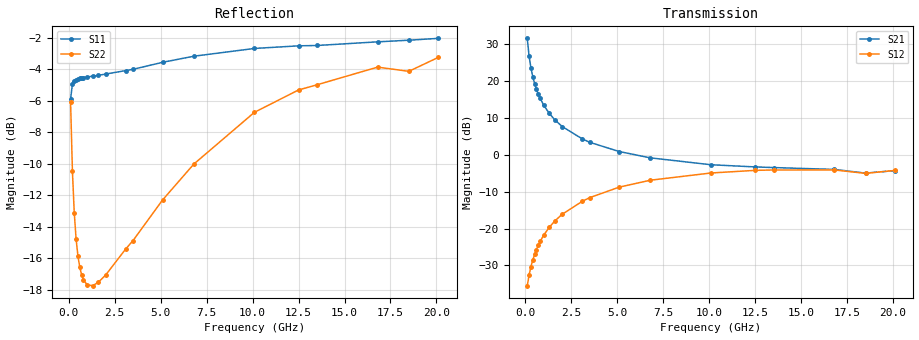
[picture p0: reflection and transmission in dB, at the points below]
!  Infineon Technologies AG
! BFR380L3 , PF131585-7, No.6, Th 09.10.01, soldered on pcb-board, measured with PP GSG850
!  Vce=2.0 V,  Ic=75.0 mA
! Common Emitter S-Parameters:  15. November 2001
#  GHz  S  MA  R  50
! f  S11  S21  S12  S22
! GHz  Mag  Ang  Mag  Ang  Mag  Ang  Mag  Ang
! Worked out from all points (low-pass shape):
!   201 points, 100 MHz to 20.1 GHz, reference 50 ohm
!   highest |S21| = 31.65 dB at 100 MHz (marker M1); lowest = -4.9 dB at 18.5 GHz (marker M2)
!   |S21| within 3 dB of the highest: start of sweep to 162.5 MHz
!   lowest |S11| = -5.9 dB at 100 MHz (marker M3), VSWR 3.05, Z = 20.3 - j22.8 ohm
!   |S11| at or under -10 dB: nowhere
!   |S22| runs from -17.8 to -3.3 dB; largest |S21 - S12| = 38
!   S11 on the Smith chart (normalised r, x): 100 MHz: 0.41, -0.46; 500 MHz: 0.26, -0.05; 3.1 GHz: 0.26, +0.35; 6.8 GHz: 0.31, +0.81; 12.5 GHz: 0.51, +1.54; 20.1 GHz: 1.02, +2.61
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0.1  0.506 -124.6  38.23 124.0  0.01677 53.5  0.496 -63.5
0.2  0.5666 -152.3  22.01 106.4  0.02333 58.2  0.2993 -87.9
0.3  0.5795 -163.6  15.17 98.8  0.03043 61.7  0.2206 -101.8
0.4  0.5844 -170.0  11.53 94.0  0.0373 65.2  0.1824 -111.8
0.5  0.5871 -174.5  9.273 90.5  0.04447 67.5  0.1611 -119.6
0.6  0.5895 -178.0  7.759 87.7  0.05198 69.1  0.1483 -125.8
0.7  0.592 179.0  6.676 85.2  0.05928 70.0  0.1406 -131.0
0.8  0.5931 176.7  5.857 82.9  0.06681 70.4  0.1353 -135.4
1  0.5949 172.2  4.714 78.9  0.08175 70.9  0.1304 -142.0
1.3  0.5993 166.5  3.655 73.4  0.1043 70.3  0.1296 -149.1
1.6  0.6024 161.3  2.998 68.4  0.1269 69.1  0.1327 -154.2
2  0.6082 155.0  2.429 62.2  0.1563 66.9  0.1399 -159.5
3.1  0.624 139.5  1.647 46.8  0.2349 59.7  0.1695 -171.7
3.5  0.6298 134.1  1.483 41.8  0.2631 56.8  0.1803 -175.0
5.1  0.6628 115.5  1.112 24.3  0.365 44.6  0.2423 168.1
6.8  0.693 98.5  0.9118 10.3  0.4536 32.2  0.315 149.7
10.1  0.7335 74.4  0.7354 -8.4  0.5685 9.8  0.46 120.7
12.5  0.7477 62.1  0.6871 -18.6  0.617 -5.0  0.5416 101.3
13.5  0.7495 57.5  0.6735 -22.4  0.6248 -10.9  0.5624 94.6
16.8  0.7698 46.1  0.6355 -33.3  0.6248 -26.4  0.6399 74.7
18.5  0.7791 44.3  0.5661 -41.0  0.562 -34.7  0.6206 69.6
20.1  0.7896 37.3  0.6124 -43.8  0.6156 -39.7  0.687 59.1
